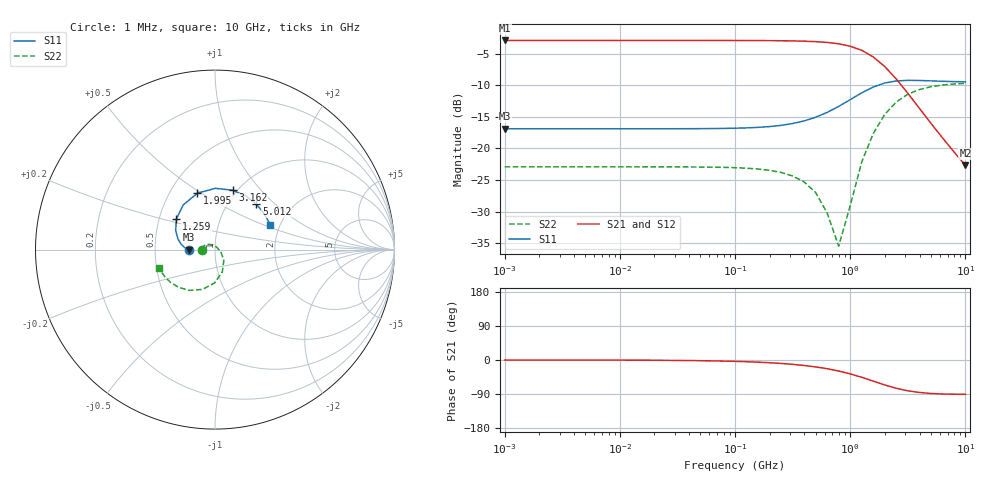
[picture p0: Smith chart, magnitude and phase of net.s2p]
! Series R-L (10 ohm, 5 nH) between the ports, 100 ohm shunt at port 1,
! series 25 ohm + 2 pF shunt at port 2. S from Y analytically, 50 ohm.
# HZ S RI R 50
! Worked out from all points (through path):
!   41 points, 1 MHz to 10 GHz, reference 50 ohm
!   highest |S21| = -2.92 dB at 1 MHz (marker M1); lowest = -22.7 dB at 10 GHz (marker M2)
!   group delay of S21, straight-line fit = 34.8 ps
!   lowest |S11| = -16.9 dB at 1 MHz (marker M3), VSWR 1.33, Z = 37.5 + j1.09e-08 ohm
!   |S11| at or under -10 dB: start of sweep to 1.774 GHz
!   |S22| runs from -35.5 to -9.7 dB; largest |S21 - S12| = 6.7e-16
!   S11 on the Smith chart (normalised r, x): 1 MHz: 0.75, +0.00; 1.259 GHz: 0.61, +0.23; 1.995 GHz: 0.68, +0.48; 3.162 GHz: 0.95, +0.72; 5.012 GHz: 1.35, +0.77; 10 GHz: 1.77, +0.55
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1000000  -0.1429 1.42e-10  0.7143 -0.000449  0.7143 -0.000449  -0.0714 8.98e-05
5011872  -0.1429 1.79e-08  0.7143 -0.00225  0.7143 -0.00225  -0.0714 0.00045
2.511886e7  -0.143 2.26e-06  0.7142 -0.0113  0.7142 -0.0113  -0.0713 0.00225
6.309573e7  -0.1435 3.57e-05  0.7135 -0.0283  0.7135 -0.0283  -0.0708 0.00563
1.258925e8  -0.1452 0.000283  0.7112 -0.0564  0.7112 -0.0564  -0.0688 0.011
1.995262e8  -0.1487 0.00112  0.7064 -0.0892  0.7064 -0.0892  -0.0649 0.0169
2.511886e8  -0.152 0.00222  0.7018 -0.112  0.7018 -0.112  -0.0611 0.0205
3.162278e8  -0.1571 0.00439  0.6945 -0.1405  0.6945 -0.1405  -0.0553 0.0244
3.981072e8  -0.1647 0.00862  0.6827 -0.1757  0.6827 -0.1757  -0.0466 0.0278
5.011872e8  -0.1755 0.0167  0.6639 -0.2186  0.6639 -0.2186  -0.0336 0.0295
6.309573e8  -0.1899 0.032  0.6341 -0.2695  0.6341 -0.2695  -0.0154 0.0267
7.943282e8  -0.2064 0.0595  0.5872 -0.3268  0.5872 -0.3268  0.00798 0.0148
1e9  -0.219 0.1051  0.5162 -0.3839  0.5162 -0.3839  0.0329 -0.0126
1.258925e9  -0.2148 0.1716  0.4171 -0.4272  0.4171 -0.4272  0.0491 -0.0605
1.584893e9  -0.1768 0.2494  0.2976 -0.4377  0.2976 -0.4377  0.0407 -0.1245
1.995262e9  -0.099 0.3137  0.1814 -0.4052  0.1814 -0.4052  -0.00214 -0.1856
2.511886e9  0.00162 0.3415  0.0937 -0.3413  0.0937 -0.3413  -0.0701 -0.222
3.162278e9  0.0984 0.331  0.0414 -0.2698  0.0414 -0.2698  -0.1419 -0.2274
3.981072e9  0.1754 0.2965  0.0157 -0.2072  0.0157 -0.2072  -0.2022 -0.2106
5.011872e9  0.2302 0.2529  0.00472 -0.1582  0.00472 -0.1582  -0.2467 -0.1833
6.309573e9  0.2671 0.2096  0.000662 -0.1214  0.000662 -0.1214  -0.2772 -0.1539
1e10  0.3065 0.1379  -0.000771 -0.0733  -0.000771 -0.0733  -0.3104 -0.1025
